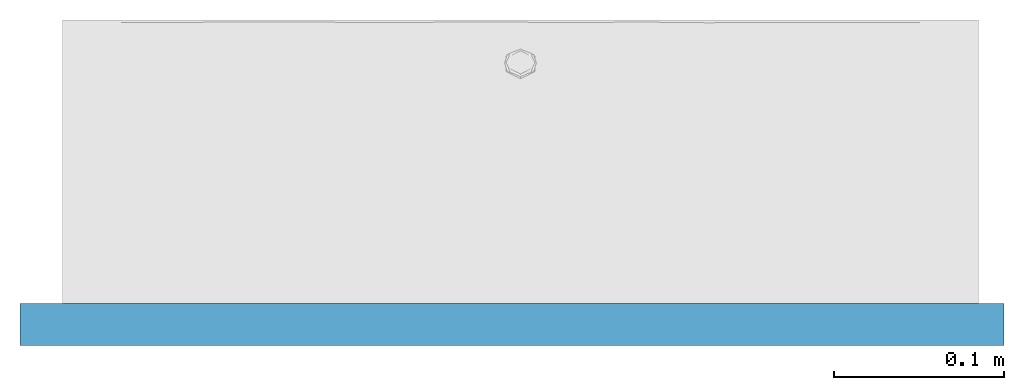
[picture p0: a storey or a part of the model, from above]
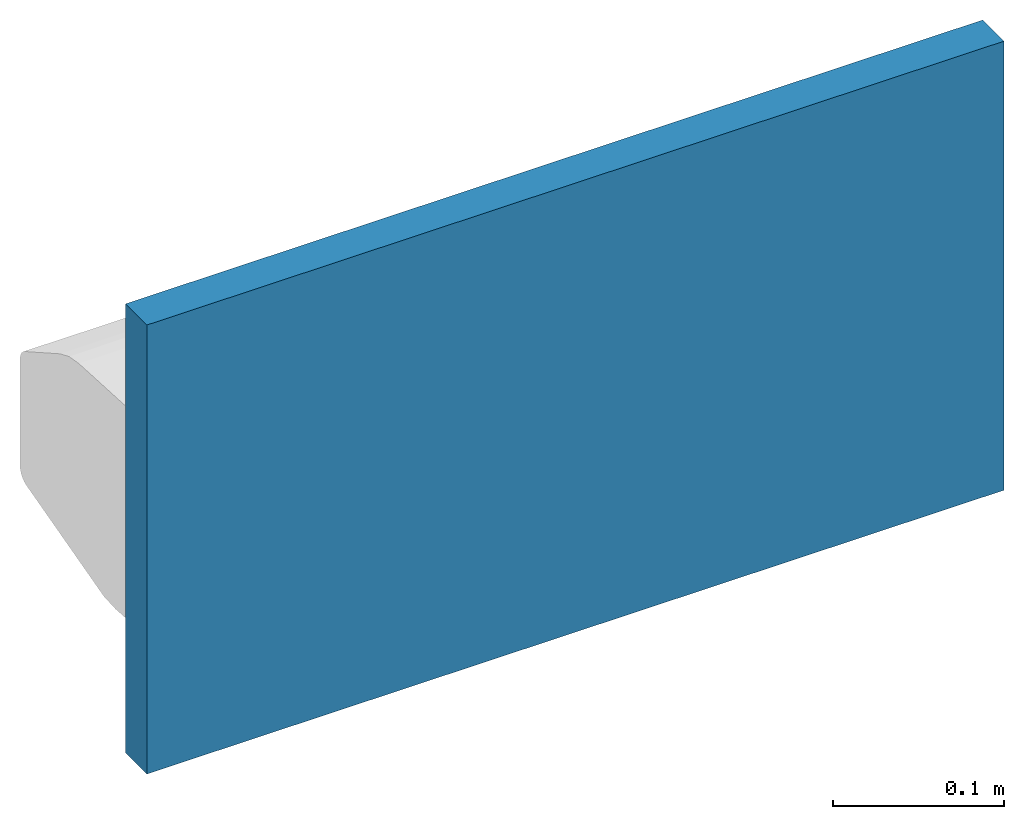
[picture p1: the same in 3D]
Properties of the parts of a building model (IFC2X3)

# File
Description: ViewDefinition [CoordinationView]
Time: 2016-04-01T14:12:16
Written by: The EXPRESS Data Manager Version 5.01.0100.02.64mod : 6 Jun 2012
Made in: 20140709_2115(x64) - Exporter 2014.0.2014.0709 - Default UI
Comment: STEP Physical File produced by: The EXPRESS Data Manager Version 5.01.0100.02.64mod : 6 Jun 2012 * Module: EDMstepFileFactory/EDMstandAlone * Creation date: Fri Apr 01 14:12:16 2016 * Host: BIM-HP * Database: C:\Users\dcole\AppData\Local\Temp\{9D22114D-B224-4E6A-98C2-051B184CD21B}\ifc * Database version: 5507 * Database creation date: Fri Apr 01 14:12:15 2016 * Schema: IFC2X3 * Model: DataRepository.ifc * Model creation date: Fri Apr 01 14:12:16 2016 * Header model: DataRepository.ifc_HeaderModel * Header model creation date: Fri Apr 01 14:12:16 2016 * EDMuser: sdai-user * EDMgroup: sdai-group * License ID and type: 5605 : Permanent license. Expiry date: * EDMstepFileFactory options: 020000

# IfcProject
LongName: P:\Fastrack\53721_BELL-CHEM\ADDITIONAL DRAWINGS 2016 BIM\IFC\BC770-20W.ifc

# IfcSite, Default
RefLatitude: 42, 24, 53, 508911; RefLongitude: -71, -15, -29, -58837; RefElevation: 0 mm

# IfcBuilding
Pset_BuildingCommon - NumberOfStoreys: 1

# IfcBuildingStorey, Level 1
LongName: Level 1; Elevation: 0 mm
Constraints - Elevation Base: Project Base Point; Elevation: 0 mm
Dimensions - Computation Height: 0 mm
Identity Data - Structural: no; Building Story: yes; Name: Level 1
Graphics - Symbol at End 1 Default: no; Line Pattern: -3000010; Color: 0; Line Weight: 1; Symbol at End 2 Default: yes

# IfcBuildingElementProxy: BC 770-20W Dolphin Couch White Metal Roll Dispenser, BC770-20W:BC 770-20W Dolphin Couch White Metal Roll Dispenser:19071
In: Level 1
Material: White Metal
Phasing - Phase Created: New Construction
Constraints - Elevation: 37.9855 mm; Level: Level: Level 1
Dimensions - Volume: 0.000689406 m3; Projection: 167mm; Capacity Roll: 20 inch width; Height: 158mm; Width: 288mm
Pset_ManufacturerTypeInformation - Manufacturer: Bell-Chem Products Co.
Pset_BuildingElementProxyCommon - Reference: BC 770-20W Dolphin Couch White Metal Roll Dispenser
Identity Data - Tel No.: +44 (0) 1424 202224; Type Comments: Also available for 10 inch width rolls; Assembly Code: D2010900; Email: info@dolphindispensers.co.uk; Fax No.: +44 (0) 1424 205200; Assembly Description: Other Plumbing Fixtures; Manufacturer: Bell-Chem Products Co.; Address line 1: Southpoint, Compass Park, Bodiam, Robertsbridge, TN32 5BS; Model: BC 770 - 20W; Description: Couch Roll Dispenser; URL: www.dolphindispensers.co.uk
Materials and Finishes - Finish: White Metal
General - Product Data: Very durable dispenser offering a wide choice of paper rolls. Serrated edges allow continuous or perforated rolls to be used. Lockable; Product Page Link: http://www.dolphindispensers.co.uk/products/bc770-dolphin-white-metal-couch-roll-dispenser/121.htm

# IfcWallStandardCase: Basic Wall:Wall 1, Basic Wall:Wall 1:3092
In: Level 1
Type - PredefinedType: STANDARD; Material: Default Wall 25 mm
Type - Construction - Width: 25 mm; Wrapping at Inserts: Do not wrap; Function: Exterior
Type - Analytical Properties - Absorptance: 0.1; Roughness: 1
Type - Graphics - Coarse Scale Fill Color: 8454143
Constraints - Location Line: Wall Centerline; Base Constraint: Level: Level 1; Room Bounding: yes; Related to Mass: no; Top Offset: 0 mm; Base is Attached: no; Top Extension Distance: 0 mm; Top is Attached: no; Base Offset: -22.7478 mm; Unconnected Height: 321.23 mm; Base Extension Distance: 0 mm
Phasing - Phase Created: New Construction
Dimensions - Area: 0.186313 m2; Volume: 0.00465783 m3; Length: 580 mm
Structural - Enable Analytical Model: no; Structural Usage: Non-bearing; Structural: no
Pset_WallCommon - Reference: Wall 1; LoadBearing: no; ExtendToStructure: no; IsExternal: yes
